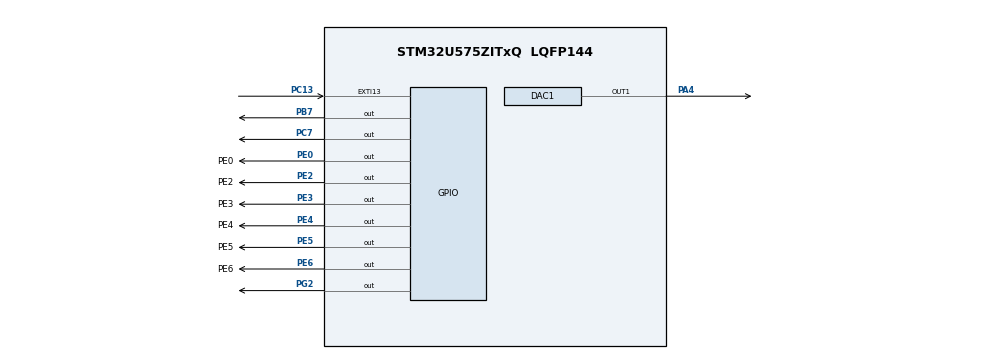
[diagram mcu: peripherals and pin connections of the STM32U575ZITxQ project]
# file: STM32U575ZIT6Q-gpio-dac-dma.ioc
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CORTEX_M33_NS.userName=CORTEX_M33
DAC1.DAC_AutonomousMode=DAC_AUTONOMOUS_MODE_DISABLE
DAC1.DAC_Channel-DAC_OUT1=DAC_CHANNEL_1
DAC1.DAC_DMADoubleDataMode-DAC_OUT1=DISABLE
DAC1.DAC_HighFrequency=DAC_HIGH_FREQUENCY_INTERFACE_MODE_DISABLE
DAC1.DAC_OutputBuffer_OUT1-DAC_OUT1=DAC_OUTPUTBUFFER_ENABLE
DAC1.DAC_SampleAndHold-DAC_OUT1=DAC_SAMPLEANDHOLD_DISABLE
DAC1.DAC_Trigger-DAC_OUT1=DAC_TRIGGER_T2_TRGO
DAC1.DAC_UserTrimming-DAC_OUT1=DAC_TRIMMING_FACTORY
GPDMA1.LINKEDLISTMODE_GPDMACH10=DMA_LINKEDLIST_CIRCULAR
GPDMA1.LINKEDLISTMODE_GPDMACH11=DMA_LINKEDLIST_CIRCULAR
GPDMA1.PRIORITY_LL_GPDMACH10=DMA_HIGH_PRIORITY
GPDMA1.PRIORITY_LL_GPDMACH11=DMA_HIGH_PRIORITY
ICACHE.Region=_NULL
Linkedlist.MDMA_Channel0.GP_SW.0.BlkHWRequest=DMA_BREQ_SINGLE_BURST
Linkedlist.MDMA_Channel0.GP_SW.0.DataHandling=NONE
Linkedlist.MDMA_Channel0.GP_SW.0.DataSize=16*4
Linkedlist.MDMA_Channel0.GP_SW.0.DestBurstLength=1
Linkedlist.MDMA_Channel0.GP_SW.0.DestDataWidth=DMA_DEST_DATAWIDTH_WORD
Linkedlist.MDMA_Channel0.GP_SW.0.DestInc=DMA_DINC_FIXED
Linkedlist.MDMA_Channel0.GP_SW.0.Direction=DMA_MEMORY_TO_PERIPH
Linkedlist.MDMA_Channel0.GP_SW.0.DstAddress=(uint32_t)&(GPIOE->ODR)
Linkedlist.MDMA_Channel0.GP_SW.0.Instance=MDMA_Channel0
Linkedlist.MDMA_Channel0.GP_SW.0.LL_CIRCULARNODE=GPIOENode
Linkedlist.MDMA_Channel0.GP_SW.0.LL_MASTERDMA=GPDMA
Linkedlist.MDMA_Channel0.GP_SW.0.LL_NAME=GPIOQueue
Linkedlist.MDMA_Channel0.GP_SW.0.LL_TYPE=CIRCULAR
Linkedlist.MDMA_Channel0.GP_SW.0.NODE_NAME=GPIOENode
Linkedlist.MDMA_Channel0.GP_SW.0.Requestforcodegen=GPDMA1_REQUEST_TIM2_UP
Linkedlist.MDMA_Channel0.GP_SW.0.SrcAddress=GPIOEVals
Linkedlist.MDMA_Channel0.GP_SW.0.SrcBurstLength=1
Linkedlist.MDMA_Channel0.GP_SW.0.SrcDataWidth=DMA_SRC_DATAWIDTH_WORD
Linkedlist.MDMA_Channel0.GP_SW.0.SrcInc=DMA_SINC_INCREMENTED
Linkedlist.MDMA_Channel0.GP_SW.0.TransferAllocatedPortDest=DMA_DEST_ALLOCATED_PORT0
Linkedlist.MDMA_Channel0.GP_SW.0.TransferAllocatedPortSrc=DMA_SRC_ALLOCATED_PORT0
Linkedlist.MDMA_Channel0.GP_SW.0.TransferEventMode=DMA_TCEM_EACH_LL_ITEM_TRANSFER
Linkedlist.MDMA_Channel0.GP_SW.0.TriggerMode=DMA_TRIGM_BLOCK_TRANSFER
Linkedlist.MDMA_Channel0.GP_SW.0.TriggerPolarity=DMA_TRIG_POLARITY_RISING
Linkedlist.MDMA_Channel0.GP_SW.0.TriggerSelection=GPDMA1_TRIGGER_TIM2_TRGO
Linkedlist.MDMA_Channel0.Request0=GP_SW
Linkedlist.MDMA_Channel0.RequestsNb=1
Linkedlist.MDMA_Channel1.GP_SW.0.BlkHWRequest=DMA_BREQ_SINGLE_BURST
Linkedlist.MDMA_Channel1.GP_SW.0.DataHandling=NONE
Linkedlist.MDMA_Channel1.GP_SW.0.DataSize=16*4
Linkedlist.MDMA_Channel1.GP_SW.0.DestBurstLength=1
Linkedlist.MDMA_Channel1.GP_SW.0.DestDataWidth=DMA_DEST_DATAWIDTH_WORD
Linkedlist.MDMA_Channel1.GP_SW.0.DestInc=DMA_DINC_FIXED
Linkedlist.MDMA_Channel1.GP_SW.0.Direction=DMA_PERIPH_TO_MEMORY
Linkedlist.MDMA_Channel1.GP_SW.0.DstAddress=(uint32_t)&(DAC1->DOR1)
Linkedlist.MDMA_Channel1.GP_SW.0.Instance=MDMA_Channel1
Linkedlist.MDMA_Channel1.GP_SW.0.LL_CIRCULARNODE=DACNode
Linkedlist.MDMA_Channel1.GP_SW.0.LL_MASTERDMA=GPDMA
Linkedlist.MDMA_Channel1.GP_SW.0.LL_NAME=DACQueue
Linkedlist.MDMA_Channel1.GP_SW.0.LL_TYPE=CIRCULAR
Linkedlist.MDMA_Channel1.GP_SW.0.NODE_NAME=DACNode
Linkedlist.MDMA_Channel1.GP_SW.0.Requestforcodegen=GPDMA1_REQUEST_DAC1_CH1
Linkedlist.MDMA_Channel1.GP_SW.0.SrcAddress=DACVals
Linkedlist.MDMA_Channel1.GP_SW.0.SrcBurstLength=1
Linkedlist.MDMA_Channel1.GP_SW.0.SrcDataWidth=DMA_SRC_DATAWIDTH_WORD
Linkedlist.MDMA_Channel1.GP_SW.0.SrcInc=DMA_SINC_INCREMENTED
Linkedlist.MDMA_Channel1.GP_SW.0.TransferAllocatedPortDest=DMA_DEST_ALLOCATED_PORT0
Linkedlist.MDMA_Channel1.GP_SW.0.TransferAllocatedPortSrc=DMA_SRC_ALLOCATED_PORT0
Linkedlist.MDMA_Channel1.GP_SW.0.TransferEventMode=DMA_TCEM_BLOCK_TRANSFER
Linkedlist.MDMA_Channel1.GP_SW.0.TriggerPolarity=DMA_TRIG_POLARITY_MASKED
Linkedlist.MDMA_Channel1.Request0=GP_SW
Linkedlist.MDMA_Channel1.RequestsNb=1
Linkedlist.RequestSet0=MDMA_Channel0
Linkedlist.RequestSet1=MDMA_Channel1
Linkedlist.RequestSetsNb=2
Mcu.Family=STM32U5
Mcu.Name=STM32U575ZITxQ
Mcu.Package=LQFP144
NUCLEO-U575ZI-Q.BUTTON=1
NUCLEO-U575ZI-Q.Bsp_Common_DEMO=true
NUCLEO-U575ZI-Q.LD1=true
NUCLEO-U575ZI-Q.LD2=true
NUCLEO-U575ZI-Q.LD3=true
NUCLEO-U575ZI-Q.VCP=true
NVIC.DAC1_IRQn=true\:0\:0\:false\:false\:true\:true\:true\:true
NVIC.EXTI13_IRQn=true\:0\:0\:false\:false\:true\:false\:true\:true
NVIC.GPDMA1_Channel10_IRQn=true\:0\:0\:false\:false\:true\:true\:true\:true
NVIC.GPDMA1_Channel11_IRQn=true\:0\:0\:false\:false\:true\:false\:true\:true
NVIC.PriorityGroup=NVIC_PRIORITYGROUP_3
NVIC.TIM17_IRQn=true\:7\:0\:false\:false\:true\:false\:true\:true
NVIC.TimeBase=TIM17_IRQn
NVIC.TimeBaseIP=TIM17
PA10.Signal=USART1_RX
PA13\ (JTMS/SWDIO).Signal=DEBUG_JTMS-SWDIO
PA14\ (JTCK/SWCLK).Signal=DEBUG_JTCK-SWCLK
PA4.Signal=COMP_DAC11_group
PA9.Signal=USART1_TX
PB3\ (JTDO/TRACESWO).Signal=DEBUG_JTDO-SWO
PB7.Signal=GPIO_Output
PC13.Signal=GPXTI13
PC14-OSC32_IN\ (PC14).Mode=LSE-External-Oscillator
PC14-OSC32_IN\ (PC14).Signal=RCC_OSC32_IN
PC15-OSC32_OUT\ (PC15).Mode=LSE-External-Oscillator
PC15-OSC32_OUT\ (PC15).Signal=RCC_OSC32_OUT
PC7.Signal=GPIO_Output
PE0.GPIO_Label=PE0
PE0.Signal=GPIO_Output
PE2.GPIO_Label=PE2
PE2.Signal=GPIO_Output
PE3.GPIO_Label=PE3
PE3.Signal=GPIO_Output
PE4.GPIO_Label=PE4
PE4.Signal=GPIO_Output
PE5.GPIO_Label=PE5
PE5.Signal=GPIO_Output
PE6.GPIO_Label=PE6
PE6.Signal=GPIO_Output
PG2.Signal=GPIO_Output
PH0-OSC_IN\ (PH0).Mode=HSE-External-Oscillator
PH0-OSC_IN\ (PH0).Signal=RCC_OSC_IN
PH1-OSC_OUT\ (PH1).Mode=HSE-External-Oscillator
PH1-OSC_OUT\ (PH1).Signal=RCC_OSC_OUT
PWR.PowerMode=PWR_SMPS_SUPPLY
ProjectManager.HeapSize=0x200
ProjectManager.StackSize=0x400
ProjectManager.TargetToolchain=STM32CubeIDE
RCC.ADCFreq_Value=16000000
RCC.AHBFreq_Value=4000000
RCC.APB1Freq_Value=4000000
RCC.APB1TimFreq_Value=4000000
RCC.APB2Freq_Value=4000000
RCC.APB2TimFreq_Value=4000000
RCC.APB3Freq_Value=4000000
RCC.CortexFreq_Value=4000000
RCC.DACCLockSelectionVirtual=RCC_DAC1CLKSOURCE_LSI
RCC.EPOD_VALUE=4000000
RCC.HCLKFreq_Value=4000000
RCC.HSE_VALUE=16000000
RCC.HSI48_VALUE=48000000
RCC.HSI_VALUE=16000000
RCC.LSIDIV_VALUE=32000
RCC.MSI_VALUE=4000000
RCC.PLL2FRACN=0
RCC.PLL3FRACN=0
RCC.PLLFRACN=0
RCC.SYSCLKFreq_VALUE=4000000
RCC.USBFreq_Value=48000000
RCC.VCOOutputFreq_Value=516000000
SH.COMP_DAC11_group.0=DAC1_OUT1,DAC_OUT1
TIM2.CounterMode=TIM_COUNTERMODE_UP
TIM2.PeriodNoDither=1
TIM2.Prescaler=20-1
TIM2.TIM_MasterOutputTrigger=TIM_TRGO_UPDATE
VP_GPDMA1_VS_GPDMACH10.Mode=LINKEDLIST_GPDMACH10
VP_GPDMA1_VS_GPDMACH11.Mode=LINKEDLIST_GPDMACH11
VP_ICACHE_VS_ENABLE_ICACHE_MEMORY.Mode=Memoryregions
VP_ICACHE_VS_ICACHE.Mode=DefaultMode
VP_LPBAMQUEUE_VS_QUEUE.Mode=QUEUEMODE
VP_LPBAM_VS_SIG1.Mode=SmartRun
VP_LPBAM_VS_SIG4.Mode=LPDMA1
VP_MEMORYMAP_VS_MEMORYMAP.Mode=CurAppReg
VP_NUCLEO-U575ZI-Q_VS_BSP_COMMON.Mode=COMMON
VP_PWR_VS_DBSignals.Mode=DisableDeadBatterySignals
VP_PWR_VS_LPOM.Mode=PowerOptimisation
VP_PWR_VS_SECSignals.Mode=Security/Privilege
VP_SYS_VS_tim17.Mode=TIM17
VP_TIM2_VS_ClockSourceINT.Mode=Internal
board=NUCLEO-U575ZI-Q

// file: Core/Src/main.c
/* USER CODE BEGIN Header */
/**
  ******************************************************************************
  * @file           : main.c
  * @brief          : Main program body
  ******************************************************************************
  * @attention
  *
  * Copyright (c) 2024 STMicroelectronics.
  * All rights reserved.
  *
  * This software is licensed under terms that can be found in the LICENSE file
  * in the root directory of this software component.
  * If no LICENSE file comes with this software, it is provided AS-IS.
  *
  ******************************************************************************
  */
/* USER CODE END Header */

#include "main.h"

/* USER CODE BEGIN Includes */
#include "st_stimulator.h"
#include "st_engine.h"
#include "st_comm.h"
#include "st_protocol.h"
#include "st_monitor.h"
#include "st_hw_config.h"
/* USER CODE END Includes */

COM_InitTypeDef BspCOMInit;
__IO uint32_t BspButtonState = BUTTON_RELEASED;

DAC_HandleTypeDef hdac1;

DMA_HandleTypeDef handle_GPDMA1_Channel11;
DMA_HandleTypeDef handle_GPDMA1_Channel10;

TIM_HandleTypeDef htim2;

/* USER CODE BEGIN PV */

/* Only referenced by the CubeMX generated linked_list.c, which is no longer
 * used (the GPDMA linked lists are never started). Remove both together with
 * the GPDMA1 linked lists in the .ioc. */
uint32_t DACVals[1];
uint32_t GPIOEVals[1];

/* USER CODE END PV */

void SystemClock_Config(void);
static void SystemPower_Config(void);
static void MX_GPIO_Init(void);
static void MX_GPDMA1_Init(void);
static void MX_ICACHE_Init(void);
static void MX_DAC1_Init(void);
static void MX_TIM2_Init(void);

int main(void)
{

  /* USER CODE BEGIN 1 */
  char line[COMM_LINE_LENGTH];
  char response[COMM_LINE_LENGTH];
  uint32_t lastCommandTick;
  uint32_t watchdog;
  int8_t received;
  /* USER CODE END 1 */

  /* MCU Configuration--------------------------------------------------------*/

  /* Reset of all peripherals, Initializes the Flash interface and the Systick. */
  HAL_Init();

  /* Configure the System Power */
  SystemPower_Config();

  /* Configure the system clock */
  SystemClock_Config();

  /* USER CODE BEGIN SysInit */
  __HAL_RCC_PWR_CLK_ENABLE();
  /* USER CODE END SysInit */

  /* Initialize all configured peripherals */
  MX_GPIO_Init();
  MX_GPDMA1_Init();
  MX_ICACHE_Init();
  MX_DAC1_Init();
  MX_TIM2_Init();
  /* USER CODE BEGIN 2 */
  /* Multiplexer outputs to the safe state as soon as possible */
  stConfigureDefault();
  stEngineInit();
  /* USER CODE END 2 */

  /* Initialize leds */
  BSP_LED_Init(LED_GREEN);
  BSP_LED_Init(LED_BLUE);
  BSP_LED_Init(LED_RED);

  /* Initialize USER push-button, will be used to trigger an interrupt each time it's pressed.*/
  BSP_PB_Init(BUTTON_USER, BUTTON_MODE_EXTI);

  /* Initialize COM1 port (115200, 8 bits (7-bit data + 1 stop bit), no parity */
  BspCOMInit.BaudRate   = 115200;
  BspCOMInit.WordLength = COM_WORDLENGTH_8B;
  BspCOMInit.StopBits   = COM_STOPBITS_1;
  BspCOMInit.Parity     = COM_PARITY_NONE;
  BspCOMInit.HwFlowCtl  = COM_HWCONTROL_NONE;
  if (BSP_COM_Init(COM1, &BspCOMInit) != BSP_ERROR_NONE)
  {
    Error_Handler();
  }

  /* USER CODE BEGIN BSP */

  /* LEDs: green = ready, blue = stimulating */
  BSP_LED_On(LED_GREEN);
  BSP_LED_Off(LED_BLUE);
  BSP_LED_Off(LED_RED);

  /* The per pulse reports need more than 115200 baud (set in the .ioc) */
  BspCOMInit.BaudRate = ST_COMM_BAUDRATE;
  if ((BSP_COM_DeInit(COM1) != BSP_ERROR_NONE) || (BSP_COM_Init(COM1, &BspCOMInit) != BSP_ERROR_NONE))
  {
    Error_Handler();
  }
  stCommInit();
  stCommWriteLine("EVT READY STIMMUX FW=" ST_FW_VERSION);
  lastCommandTick = HAL_GetTick();
  /* USER CODE END BSP */

  /* Infinite loop */
  /* USER CODE BEGIN WHILE */
  while (1)
  {

    /* User push-button: local stop */
    if (BspButtonState == BUTTON_PRESSED)
    {
      BspButtonState = BUTTON_RELEASED;
      if (stEngineIsRunning())
      {
        stEngineStop();
        stCommWriteLine("EVT STOP BUTTON");
      }
    }
    /* USER CODE END WHILE */

    /* USER CODE BEGIN 3 */
    received = stCommReadLine(line, sizeof(line));
    if (received != 0)
    {
      lastCommandTick = HAL_GetTick();
      if (received > 0)
        stProtocolHandleLine(line, response, sizeof(response));
      else
        snprintf(response, sizeof(response), "ERR LENGTH");
      stCommWriteLine(response);
    }

    /* Current monitor: per pulse statistics and waveform requests */
    stMonitorProcess();

    if (stEngineTakeDoneFlag())
    {
      snprintf(response, sizeof(response), "EVT DONE FRAMES=%lu", (unsigned long)stEngineFrameCount());
      stCommWriteLine(response);
    }

    /* Host watchdog: stop if the controller stops sending commands */
    watchdog = stProtocolGetWatchdog();
    if ((watchdog != 0U) && stEngineIsRunning() && ((HAL_GetTick() - lastCommandTick) > watchdog))
    {
      stEngineStop();
      stCommWriteLine("EVT WDOG");
    }

    if (stEngineIsRunning())
      BSP_LED_On(LED_BLUE);
    else
      BSP_LED_Off(LED_BLUE);
  }
  /* USER CODE END 3 */
}

void SystemClock_Config(void)
{
  RCC_OscInitTypeDef RCC_OscInitStruct = {0};
  RCC_ClkInitTypeDef RCC_ClkInitStruct = {0};

  /** Configure the main internal regulator output voltage
  */
  if (HAL_PWREx_ControlVoltageScaling(PWR_REGULATOR_VOLTAGE_SCALE1) != HAL_OK)
  {
    Error_Handler();
  }

  /** Initializes the CPU, AHB and APB buses clocks
  * SYSCLK = MSI 4 MHz / M(1) * N(80) / R(2) = 160 MHz
  */
  RCC_OscInitStruct.OscillatorType = RCC_OSCILLATORTYPE_HSI|RCC_OSCILLATORTYPE_LSI
                              |RCC_OSCILLATORTYPE_MSI;
  RCC_OscInitStruct.HSIState = RCC_HSI_ON;
  RCC_OscInitStruct.HSICalibrationValue = RCC_HSICALIBRATION_DEFAULT;
  RCC_OscInitStruct.LSIState = RCC_LSI_ON;
  RCC_OscInitStruct.MSIState = RCC_MSI_ON;
  RCC_OscInitStruct.MSICalibrationValue = RCC_MSICALIBRATION_DEFAULT;
  RCC_OscInitStruct.MSIClockRange = RCC_MSIRANGE_4;
  RCC_OscInitStruct.LSIDiv = RCC_LSI_DIV1;
  RCC_OscInitStruct.PLL.PLLState = RCC_PLL_ON;
  RCC_OscInitStruct.PLL.PLLSource = RCC_PLLSOURCE_MSI;
  RCC_OscInitStruct.PLL.PLLMBOOST = RCC_PLLMBOOST_DIV1;
  RCC_OscInitStruct.PLL.PLLM = 1;
  RCC_OscInitStruct.PLL.PLLN = 80;
  RCC_OscInitStruct.PLL.PLLP = 2;
  RCC_OscInitStruct.PLL.PLLQ = 2;
  RCC_OscInitStruct.PLL.PLLR = 2;
  RCC_OscInitStruct.PLL.PLLRGE = RCC_PLLVCIRANGE_0;
  RCC_OscInitStruct.PLL.PLLFRACN = 0;
  if (HAL_RCC_OscConfig(&RCC_OscInitStruct) != HAL_OK)
  {
    Error_Handler();
  }

  /** Initializes the CPU, AHB and APB buses clocks
  */
  RCC_ClkInitStruct.ClockType = RCC_CLOCKTYPE_HCLK|RCC_CLOCKTYPE_SYSCLK
                              |RCC_CLOCKTYPE_PCLK1|RCC_CLOCKTYPE_PCLK2
                              |RCC_CLOCKTYPE_PCLK3;
  RCC_ClkInitStruct.SYSCLKSource = RCC_SYSCLKSOURCE_PLLCLK;
  RCC_ClkInitStruct.AHBCLKDivider = RCC_SYSCLK_DIV1;
  RCC_ClkInitStruct.APB1CLKDivider = RCC_HCLK_DIV1;
  RCC_ClkInitStruct.APB2CLKDivider = RCC_HCLK_DIV1;
  RCC_ClkInitStruct.APB3CLKDivider = RCC_HCLK_DIV1;

  if (HAL_RCC_ClockConfig(&RCC_ClkInitStruct, FLASH_LATENCY_4) != HAL_OK)
  {
    Error_Handler();
  }
}

/**
  * @brief Power Configuration
  * @retval None
  */
static void SystemPower_Config(void)
{

  /*
   * Disable the internal Pull-Up in Dead Battery pins of UCPD peripheral
   */
  HAL_PWREx_DisableUCPDDeadBattery();

  /*
   * Switch to SMPS regulator instead of LDO
   */
  if (HAL_PWREx_ConfigSupply(PWR_SMPS_SUPPLY) != HAL_OK)
  {
    Error_Handler();
  }
}

static void MX_DAC1_Init(void)
{

  DAC_ChannelConfTypeDef sConfig = {0};
  DAC_AutonomousModeConfTypeDef sAutonomousMode = {0};

  /** DAC Initialization
  */
  hdac1.Instance = DAC1;
  if (HAL_DAC_Init(&hdac1) != HAL_OK)
  {
    Error_Handler();
  }

  /** DAC channel OUT1 config
  */
  sConfig.DAC_HighFrequency = DAC_HIGH_FREQUENCY_INTERFACE_MODE_DISABLE;
  sConfig.DAC_DMADoubleDataMode = DISABLE;
  sConfig.DAC_SignedFormat = DISABLE;
  sConfig.DAC_SampleAndHold = DAC_SAMPLEANDHOLD_DISABLE;
  sConfig.DAC_Trigger = DAC_TRIGGER_T2_TRGO;
  sConfig.DAC_OutputBuffer = DAC_OUTPUTBUFFER_ENABLE;
  sConfig.DAC_ConnectOnChipPeripheral = DAC_CHIPCONNECT_EXTERNAL;
  sConfig.DAC_UserTrimming = DAC_TRIMMING_FACTORY;
  if (HAL_DAC_ConfigChannel(&hdac1, &sConfig, DAC_CHANNEL_1) != HAL_OK)
  {
    Error_Handler();
  }

  /** Configure Autonomous Mode
  */
  sAutonomousMode.AutonomousModeState = DAC_AUTONOMOUS_MODE_DISABLE;
  if (HAL_DACEx_SetConfigAutonomousMode(&hdac1, &sAutonomousMode) != HAL_OK)
  {
    Error_Handler();
  }
  /* USER CODE BEGIN DAC1_Init 2 */

  HAL_DACEx_SelfCalibrate(&hdac1, &sConfig, DAC_CHANNEL_1);
  /* USER CODE END DAC1_Init 2 */

}

static void MX_GPDMA1_Init(void)
{

  /* Peripheral clock enable */
  __HAL_RCC_GPDMA1_CLK_ENABLE();

  /* GPDMA1 interrupt Init */
    HAL_NVIC_SetPriority(GPDMA1_Channel10_IRQn, 0, 0);
    HAL_NVIC_EnableIRQ(GPDMA1_Channel10_IRQn);
    HAL_NVIC_SetPriority(GPDMA1_Channel11_IRQn, 0, 0);
    HAL_NVIC_EnableIRQ(GPDMA1_Channel11_IRQn);

  handle_GPDMA1_Channel11.Instance = GPDMA1_Channel11;
  handle_GPDMA1_Channel11.InitLinkedList.Priority = DMA_HIGH_PRIORITY;
  handle_GPDMA1_Channel11.InitLinkedList.LinkStepMode = DMA_LSM_FULL_EXECUTION;
  handle_GPDMA1_Channel11.InitLinkedList.LinkAllocatedPort = DMA_LINK_ALLOCATED_PORT0;
  handle_GPDMA1_Channel11.InitLinkedList.TransferEventMode = DMA_TCEM_LAST_LL_ITEM_TRANSFER;
  handle_GPDMA1_Channel11.InitLinkedList.LinkedListMode = DMA_LINKEDLIST_CIRCULAR;
  if (HAL_DMAEx_List_Init(&handle_GPDMA1_Channel11) != HAL_OK)
  {
    Error_Handler();
  }
  if (HAL_DMA_ConfigChannelAttributes(&handle_GPDMA1_Channel11, DMA_CHANNEL_NPRIV) != HAL_OK)
  {
    Error_Handler();
  }
  handle_GPDMA1_Channel10.Instance = GPDMA1_Channel10;
  handle_GPDMA1_Channel10.InitLinkedList.Priority = DMA_HIGH_PRIORITY;
  handle_GPDMA1_Channel10.InitLinkedList.LinkStepMode = DMA_LSM_FULL_EXECUTION;
  handle_GPDMA1_Channel10.InitLinkedList.LinkAllocatedPort = DMA_LINK_ALLOCATED_PORT0;
  handle_GPDMA1_Channel10.InitLinkedList.TransferEventMode = DMA_TCEM_LAST_LL_ITEM_TRANSFER;
  handle_GPDMA1_Channel10.InitLinkedList.LinkedListMode = DMA_LINKEDLIST_CIRCULAR;
  if (HAL_DMAEx_List_Init(&handle_GPDMA1_Channel10) != HAL_OK)
  {
    Error_Handler();
  }
  if (HAL_DMA_ConfigChannelAttributes(&handle_GPDMA1_Channel10, DMA_CHANNEL_NPRIV) != HAL_OK)
  {
    Error_Handler();
  }

}

static void MX_ICACHE_Init(void)
{

  /** Enable instruction cache (default 2-ways set associative cache)
  */
  if (HAL_ICACHE_Enable() != HAL_OK)
  {
    Error_Handler();
  }

}

static void MX_TIM2_Init(void)
{

  TIM_ClockConfigTypeDef sClockSourceConfig = {0};
  TIM_MasterConfigTypeDef sMasterConfig = {0};

  /* USER CODE BEGIN TIM2_Init 1 */
  /* Prescaler, period and interrupts are reconfigured by stEngineInit() */
  /* USER CODE END TIM2_Init 1 */
  htim2.Instance = TIM2;
  htim2.Init.Prescaler = 20-1;
  htim2.Init.CounterMode = TIM_COUNTERMODE_UP;
  htim2.Init.Period = 1;
  htim2.Init.ClockDivision = TIM_CLOCKDIVISION_DIV1;
  htim2.Init.AutoReloadPreload = TIM_AUTORELOAD_PRELOAD_DISABLE;
  if (HAL_TIM_Base_Init(&htim2) != HAL_OK)
  {
    Error_Handler();
  }
  sClockSourceConfig.ClockSource = TIM_CLOCKSOURCE_INTERNAL;
  if (HAL_TIM_ConfigClockSource(&htim2, &sClockSourceConfig) != HAL_OK)
  {
    Error_Handler();
  }
  sMasterConfig.MasterOutputTrigger = TIM_TRGO_UPDATE;
  sMasterConfig.MasterSlaveMode = TIM_MASTERSLAVEMODE_DISABLE;
  if (HAL_TIMEx_MasterConfigSynchronization(&htim2, &sMasterConfig) != HAL_OK)
  {
    Error_Handler();
  }

}

static void MX_GPIO_Init(void)
{
  GPIO_InitTypeDef GPIO_InitStruct = {0};

  /* GPIO Ports Clock Enable */
  __HAL_RCC_GPIOE_CLK_ENABLE();
  __HAL_RCC_GPIOC_CLK_ENABLE();
  __HAL_RCC_GPIOH_CLK_ENABLE();
  __HAL_RCC_GPIOA_CLK_ENABLE();
  __HAL_RCC_GPIOB_CLK_ENABLE();

  /*Configure GPIO pin Output Level */
  HAL_GPIO_WritePin(GPIOE, PE2_Pin|PE3_Pin|PE4_Pin|PE5_Pin
                          |PE6_Pin|PE0_Pin, GPIO_PIN_RESET);

  /*Configure GPIO pins : PE2_Pin PE3_Pin PE4_Pin PE5_Pin
                           PE6_Pin PE0_Pin */
  GPIO_InitStruct.Pin = PE2_Pin|PE3_Pin|PE4_Pin|PE5_Pin
                          |PE6_Pin|PE0_Pin;
  GPIO_InitStruct.Mode = GPIO_MODE_OUTPUT_PP;
  GPIO_InitStruct.Pull = GPIO_NOPULL;
  GPIO_InitStruct.Speed = GPIO_SPEED_FREQ_LOW;
  HAL_GPIO_Init(GPIOE, &GPIO_InitStruct);

}

void HAL_TIM_PeriodElapsedCallback(TIM_HandleTypeDef *htim)
{
  if (htim->Instance == TIM17) {
    HAL_IncTick();
  }
}

/**
  * @brief BSP Push Button callback
  * @param Button Specifies the pressed button
  * @retval None
  */
void BSP_PB_Callback(Button_TypeDef Button)
{
  if (Button == BUTTON_USER)
  {
    BspButtonState = BUTTON_PRESSED;
  }
}

void Error_Handler(void)
{
  /* USER CODE BEGIN Error_Handler_Debug */
  /* User can add his own implementation to report the HAL error return state */
  __disable_irq();
  stEngineEmergencyStop();
  while (1)
  {
  }
  /* USER CODE END Error_Handler_Debug */
}
